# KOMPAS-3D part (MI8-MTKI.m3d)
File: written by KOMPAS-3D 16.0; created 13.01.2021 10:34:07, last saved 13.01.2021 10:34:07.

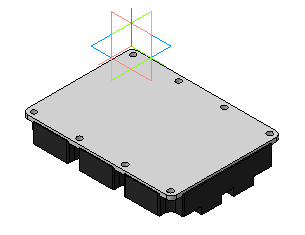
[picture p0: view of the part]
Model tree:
1. Операция без истории:1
